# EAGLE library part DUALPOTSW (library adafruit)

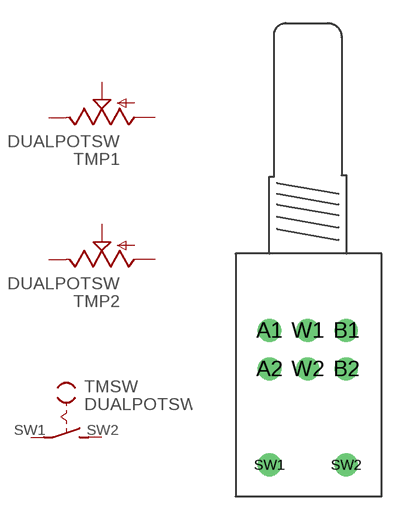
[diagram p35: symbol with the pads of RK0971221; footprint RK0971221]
Designator prefix TM; gates SW=SW P2=POT P1=POT

## DUALPOTSW  [RK0971221]
A1  P1:E  pas
A2  P2:E  pas
B1  P1:A  pas
B2  P2:A  pas
SW1  SW:P  pas
SW2  SW:S  pas
W1  P1:S  pas
W2  P2:S  pas

## Footprint RK0971221 (pad centres in mm)
drill 1 round: A1 -2.5,-5; A2 -2.5,-7.5; B1 2.5,-5; B2 2.5,-7.5; SW1 -2.5,-13.75; SW2 2.5,-13.75; W1 0,-5; W2 0,-7.5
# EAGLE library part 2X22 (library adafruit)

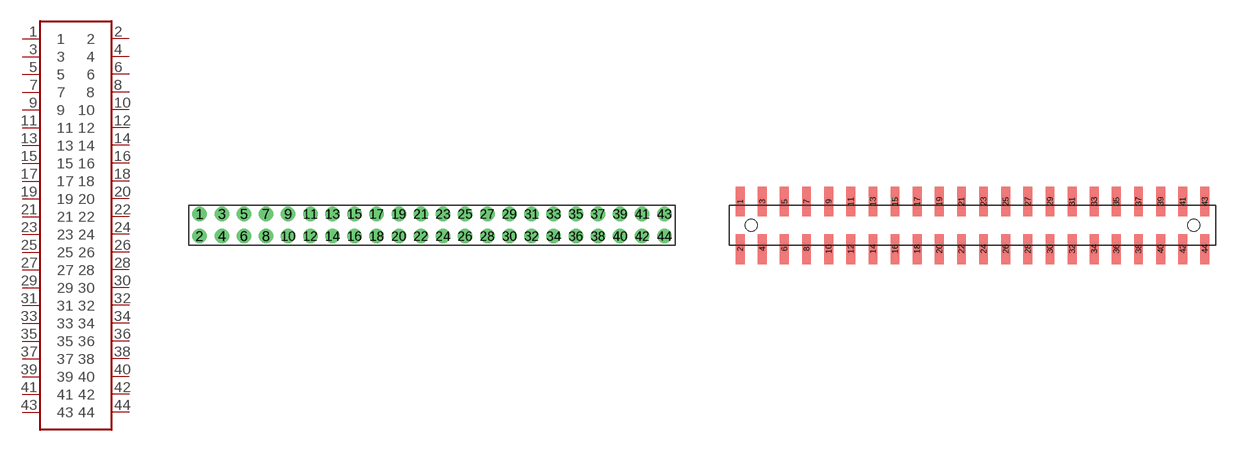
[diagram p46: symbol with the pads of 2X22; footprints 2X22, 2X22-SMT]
Designator prefix -

## 2X22-2MM  [2X22]
1  1
2  2
3  3
4  4
5  5
6  6
7  7
8  8
9  9
10  10
11  11
12  12
13  13
14  14
15  15
16  16
17  17
18  18
19  19
20  20
21  21
22  22
23  23
24  24
25  25
26  26
27  27
28  28
29  29
30  30
31  31
32  32
33  33
34  34
35  35
36  36
37  37
38  38
39  39
40  40
41  41
42  42
43  43
44  44

## 2X22-SMT  [2X22-SMT]
Pads as for 2X22

## Footprint 2X22 (pad centres in mm)
drill 0.8 round: 1 -21,1; 2 -21,-1; 3 -19,1; 4 -19,-1; 5 -17,1; 6 -17,-1; 7 -15,1; 8 -15,-1; 9 -13,1; 10 -13,-1; 11 -11,1; 12 -11,-1; 13 -9,1; 14 -9,-1; 15 -7,1; 16 -7,-1; 17 -5,1; 18 -5,-1; 19 -3,1; 20 -3,-1; 21 -1,1; 22 -1,-1; 23 1,1; 24 1,-1; 25 3,1; 26 3,-1; 27 5,1; 28 5,-1; 29 7,1; 30 7,-1; 31 9,1; 32 9,-1; 33 11,1; 34 11,-1; 35 13,1; 36 13,-1; 37 15,1; 38 15,-1; 39 17,1; 40 17,-1; 41 19,1; 42 19,-1; 43 21,1; 44 21,-1

## Footprint 2X22-SMT (pad centres in mm)
smd 0.8 x 2.7: 1 -21,2.15; 2 -21,-2.15; 3 -19,2.15; 4 -19,-2.15; 5 -17,2.15; 6 -17,-2.15; 7 -15,2.15; 8 -15,-2.15; 9 -13,2.15; 10 -13,-2.15; 11 -11,2.15; 12 -11,-2.15; 13 -9,2.15; 14 -9,-2.15; 15 -7,2.15; 16 -7,-2.15; 17 -5,2.15; 18 -5,-2.15; 19 -3,2.15; 20 -3,-2.15; 21 -1,2.15; 22 -1,-2.15; 23 1,2.15; 24 1,-2.15; 25 3,2.15; 26 3,-2.15; 27 5,2.15; 28 5,-2.15; 29 7,2.15; 30 7,-2.15; 31 9,2.15; 32 9,-2.15; 33 11,2.15; 34 11,-2.15; 35 13,2.15; 36 13,-2.15; 37 15,2.15; 38 15,-2.15; 39 17,2.15; 40 17,-2.15; 41 19,2.15; 42 19,-2.15; 43 21,2.15; 44 21,-2.15
hole 1.1 at -20,0
hole 1.1 at 20,0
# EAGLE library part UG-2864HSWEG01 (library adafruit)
UG-2864HSWEG01 OLED display

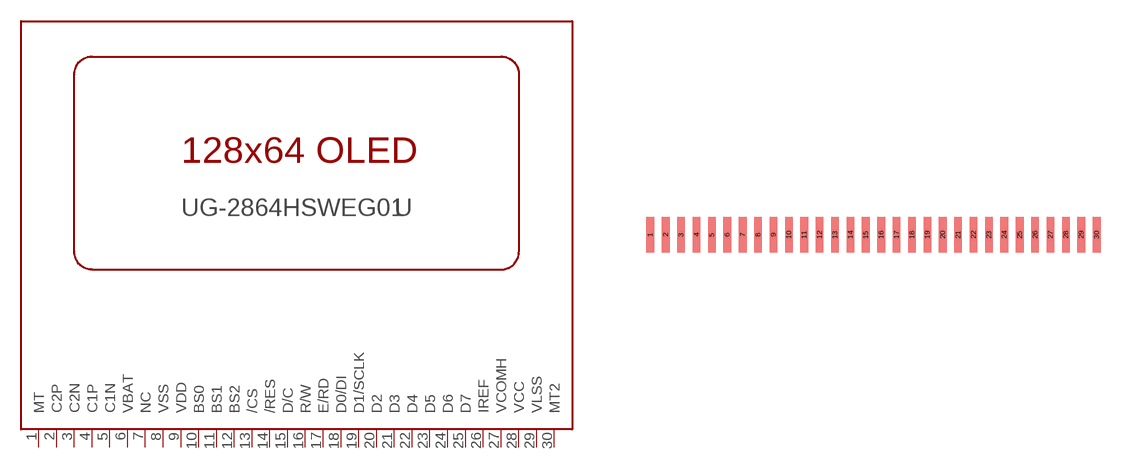
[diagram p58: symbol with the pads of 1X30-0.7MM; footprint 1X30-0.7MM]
Designator prefix -

## UG-2864HSWEG01  [1X30-0.7MM]
1  MT  in
2  C2P  in
3  C2N  in
4  C1P  in
5  C1N  in
6  VBAT  in
7  NC  nc
8  VSS  pwr
9  VDD  pwr
10  BS0  in
11  BS1  in
12  BS2  in
13  /CS  in
14  /RES  in
15  D/C  in
16  R/W  in
17  E/RD  in
18  D0/DI
19  D1/SCLK
20  D2
21  D3
22  D4
23  D5
24  D6
25  D7
26  IREF  in
27  VCOMH  out
28  VCC  pwr
29  VLSS  pwr
30  MT2  in

## Footprint 1X30-0.7MM (pad centres in mm)
smd 0.35 x 1.6: 1 -10.15,0; 2 -9.45,0; 3 -8.75,0; 4 -8.05,0; 5 -7.35,0; 6 -6.65,0; 7 -5.95,0; 8 -5.25,0; 9 -4.55,0; 10 -3.85,0; 11 -3.15,0; 12 -2.45,0; 13 -1.75,0; 14 -1.05,0; 15 -0.35,0; 16 0.35,0; 17 1.05,0; 18 1.75,0; 19 2.45,0; 20 3.15,0; 21 3.85,0; 22 4.55,0; 23 5.25,0; 24 5.95,0; 25 6.65,0; 26 7.35,0; 27 8.05,0; 28 8.75,0; 29 9.45,0; 30 10.15,0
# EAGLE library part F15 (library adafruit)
SUB-D HDH is also known as a 'right angle VGA' connector

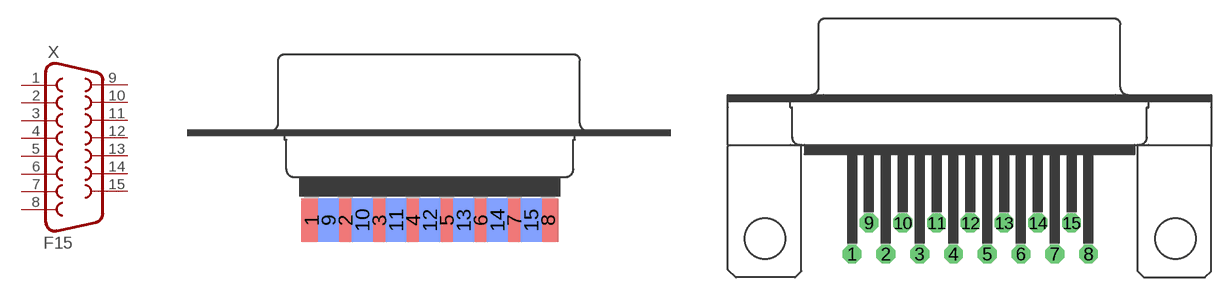
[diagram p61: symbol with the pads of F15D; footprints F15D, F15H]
Designator prefix X

## F15D  [F15D]
1  1  pas
2  2  pas
3  3  pas
4  4  pas
5  5  pas
6  6  pas
7  7  pas
8  8  pas
9  9  pas
10  10  pas
11  11  pas
12  12  pas
13  13  pas
14  14  pas
15  15  pas

## F15H  [F15H]
Pads as for F15D

## F15HP  [F15HP]
Pads as for F15D

## F15V  [F15V]
Pads as for F15D

## F15VP  [F15VP]
Pads as for F15D

## F15HDV  [HDF15V]
Pads as for F15D

## F15VB  [F15VB]
Pads as for F15D

## F15HDH  [HDF15H]
Pads as for F15D

## Footprint F15D (pad centres in mm)
SUB-D
smd 1.7 x 3.5: 1 -9.601,-6.045; 2 -6.858,-6.045; 3 -4.115,-6.045; 4 -1.372,-6.045; 5 1.372,-6.045; 6 4.115,-6.045; 7 6.858,-6.045; 8 9.601,-6.045
smd 1.7 x 3.5 bottom: 9 -8.23,-6.045; 10 -5.486,-6.045; 11 -2.743,-6.045; 12 0,-6.045; 13 2.743,-6.045; 14 5.486,-6.045; 15 8.23,-6.045

## Footprint F15H (pad centres in mm)
SUB-D
drill 1.016 octagon: 1 -9.601,-1.27; 2 -6.858,-1.27; 3 -4.115,-1.27; 4 -1.372,-1.27; 5 1.372,-1.27; 6 4.115,-1.27; 7 6.858,-1.27; 8 9.601,-1.27; 9 -8.23,1.27; 10 -5.486,1.27; 11 -2.743,1.27; 12 0,1.27; 13 2.743,1.27; 14 5.486,1.27; 15 8.23,1.27
hole 3.302 at -16.662,0
hole 3.302 at 16.662,0

## Footprint F15HP (pad centres in mm)
SUB-D
drill 1.016 octagon: 1 -9.601,-1.27; 2 -6.858,-1.27; 3 -4.115,-1.27; 4 -1.372,-1.27; 5 1.372,-1.27; 6 4.115,-1.27; 7 6.858,-1.27; 8 9.601,-1.27; 9 -8.23,1.27; 10 -5.486,1.27; 11 -2.743,1.27; 12 0,1.27; 13 2.743,1.27; 14 5.486,1.27; 15 8.23,1.27
drill 3.302 pad 5.08 round: G1 -16.662,0; G2 16.662,0

## Footprint F15V (pad centres in mm)
SUB-D
drill 1.016 octagon: 1 9.601,1.422; 2 6.858,1.422; 3 4.115,1.422; 4 1.372,1.422; 5 -1.372,1.422; 6 -4.115,1.422; 7 -6.858,1.422; 8 -9.601,1.422; 9 8.23,-1.422; 10 5.486,-1.422; 11 2.743,-1.422; 12 0,-1.422; 13 -2.743,-1.422; 14 -5.486,-1.422; 15 -8.23,-1.422
hole 3.302 at 16.662,0
hole 3.302 at -16.662,0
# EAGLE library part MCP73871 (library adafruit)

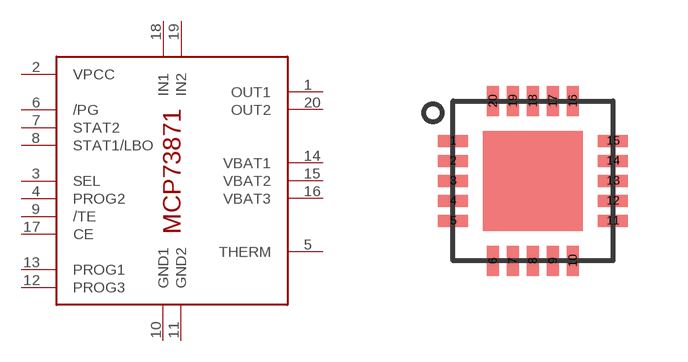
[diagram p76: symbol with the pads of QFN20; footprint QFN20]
Designator prefix IC

## MCP73871  [QFN20]
1  OUT1  out
2  VPCC  in
3  SEL  in
4  PROG2  in
5  THERM  in
6  /PG  out
7  STAT2  out
8  STAT1/LBO  out
9  /TE  in
10  GND1  pwr
11  GND2  pwr
12  PROG3  in
13  PROG1  in
14  VBAT1  out
15  VBAT2  out
16  VBAT3  out
17  CE  in
18  IN1  in
19  IN2  in
20  OUT2  out

## Footprint QFN20 (pad centres in mm)
smd 0.75 x 0.3: 1 -2,1; 2 -2,0.5; 3 -2,0; 4 -2,-0.5; 5 -2,-1; 11 2,-1; 12 2,-0.5; 13 2,0; 14 2,0.5; 15 2,1
smd 0.3 x 0.75: 6 -1,-2; 7 -0.5,-2; 8 0,-2; 9 0.5,-2; 10 1,-2; 16 1,2; 17 0.5,2; 18 0,2; 19 -0.5,2; 20 -1,2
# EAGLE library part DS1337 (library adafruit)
DS1337 - Maxim RTC without battery backup

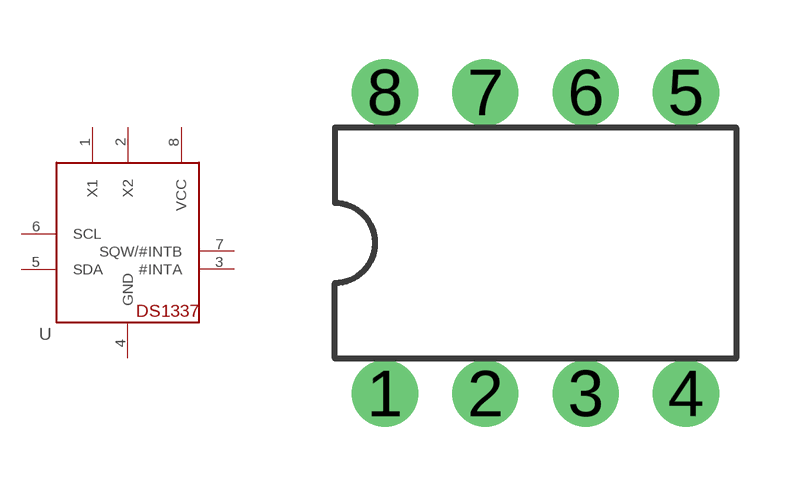
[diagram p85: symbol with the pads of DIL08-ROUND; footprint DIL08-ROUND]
Designator prefix -

## DS1337  [DIL08-ROUND]
1  X1  pas
2  X2  pas
3  #INTA  out
4  GND  pwr
5  SDA
6  SCL
7  SQW/#INTB  out
8  VCC  pwr

## Footprint DIL08-ROUND (pad centres in mm)
Dual In Line Package
drill 0.813 pad 1.676 round: 1 -3.81,-3.81; 2 -1.27,-3.81; 3 1.27,-3.81; 4 3.81,-3.81; 5 3.81,3.81; 6 1.27,3.81; 7 -1.27,3.81; 8 -3.81,3.81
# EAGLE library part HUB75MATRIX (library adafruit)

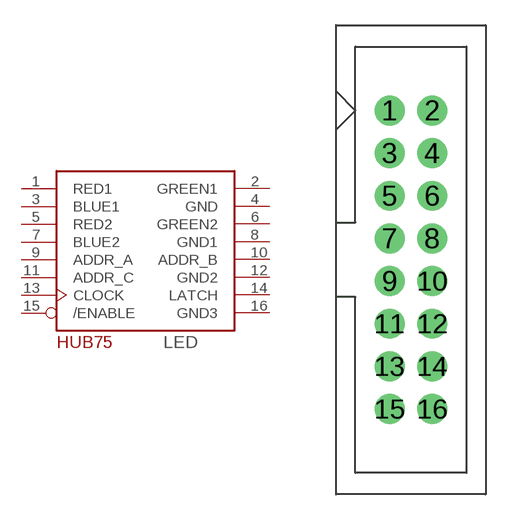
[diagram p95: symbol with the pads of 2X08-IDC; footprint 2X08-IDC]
Designator prefix LED

## HUB75MATRIX  [2X08-IDC]
1  RED1  in
2  GREEN1  in
3  BLUE1  in
4  GND  pwr
5  RED2  in
6  GREEN2  in
7  BLUE2  in
8  GND1  pwr
9  ADDR_A  in
10  ADDR_B  in
11  ADDR_C  in
12  GND2  pwr
13  CLOCK  in
14  LATCH  in
15  /ENABLE  in
16  GND3  pwr

## Footprint 2X08-IDC (pad centres in mm)
drill 1 pad 1.778 round: 1 -1.27,8.89; 2 1.27,8.89; 3 -1.27,6.35; 4 1.27,6.35; 5 -1.27,3.81; 6 1.27,3.81; 7 -1.27,1.27; 8 1.27,1.27; 9 -1.27,-1.27; 10 1.27,-1.27; 11 -1.27,-3.81; 12 1.27,-3.81; 13 -1.27,-6.35; 14 1.27,-6.35; 15 -1.27,-8.89; 16 1.27,-8.89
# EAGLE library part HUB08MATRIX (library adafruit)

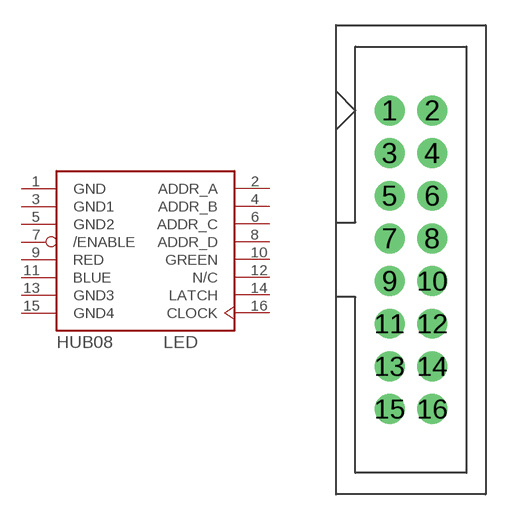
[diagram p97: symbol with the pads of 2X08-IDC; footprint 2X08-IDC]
Designator prefix LED

## HUB08MATRIX  [2X08-IDC]
1  GND  pwr
2  ADDR_A  in
3  GND1  pwr
4  ADDR_B  in
5  GND2  pwr
6  ADDR_C  in
7  /ENABLE  in
8  ADDR_D  in
9  RED  in
10  GREEN  in
11  BLUE  in
12  N/C  nc
13  GND3  pwr
14  LATCH  in
15  GND4  pwr
16  CLOCK  in

## Footprint 2X08-IDC (pad centres in mm)
drill 1 pad 1.778 round: 1 -1.27,8.89; 2 1.27,8.89; 3 -1.27,6.35; 4 1.27,6.35; 5 -1.27,3.81; 6 1.27,3.81; 7 -1.27,1.27; 8 1.27,1.27; 9 -1.27,-1.27; 10 1.27,-1.27; 11 -1.27,-3.81; 12 1.27,-3.81; 13 -1.27,-6.35; 14 1.27,-6.35; 15 -1.27,-8.89; 16 1.27,-8.89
